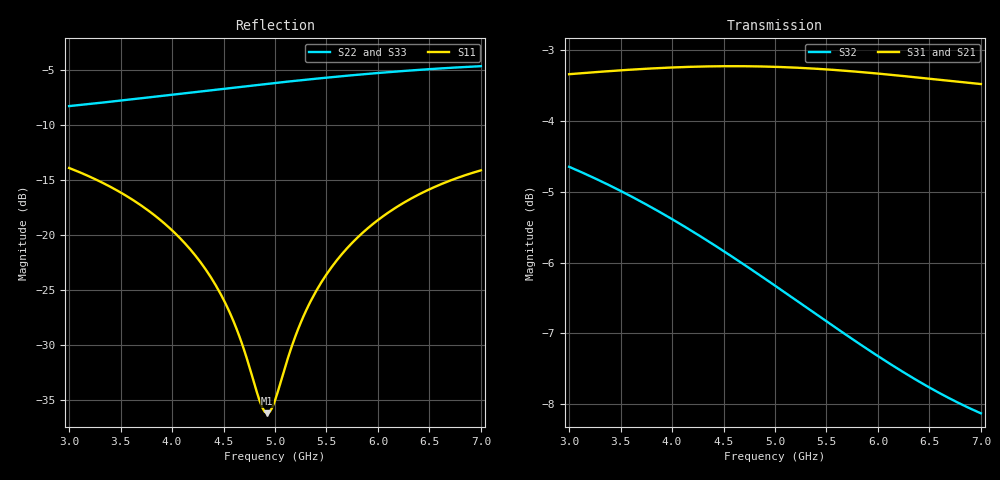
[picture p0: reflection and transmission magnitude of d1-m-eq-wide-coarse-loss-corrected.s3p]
! yapnr Order 0 prediction d1-m-eq-wide-coarse: predictions/D1/variants/d1-star-m-eq/coarse_dense.s3p, loss-corrected
! substrate M-eq; coupon model OSHPARK-4L-FR408HR; correction: ratio (port line)
! |S21|, |S31| (and S12, S13) scaled, phases kept; 50 ohm, e^(+jwt)
# GHz S RI R 50
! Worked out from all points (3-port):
!   161 points, 3 GHz to 7 GHz, reference 50 ohm
!   strongest paths, dB at 3 GHz, 4 GHz, 5 GHz, 6 GHz, 7 GHz:
!     S31: -3.3, -3.2, -3.2, -3.3, -3.5
!     S21: -3.3, -3.2, -3.2, -3.3, -3.5
!     S32: -4.6, -5.4, -6.3, -7.3, -8.1
!   lowest |S11| = -36.2 dB at 4.925 GHz (marker M1), VSWR 1.03, Z = 48.5 + j0.238 ohm
!   |S11| at or under -10 dB: start of sweep to end of sweep
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3  -0.1221 0.1605  0.1067 -0.6724  0.1067 -0.6724
   0.1066 -0.6723  0.0917 0.3747  -0.1498 -0.5661
   0.1066 -0.6723  -0.1498 -0.5661  0.0917 0.3747
3.7  -0.0571 0.1237  -0.1265 -0.6748  -0.1265 -0.6748
     -0.1265 -0.6747  0.2541 0.333  -0.3444 -0.4331
     -0.1265 -0.6747  -0.3444 -0.4331  0.2541 0.333
4.225  -0.0247 0.0769  -0.2971 -0.6219  -0.2971 -0.6219
       -0.2971 -0.6218  0.3648 0.2586  -0.4346 -0.296
       -0.2971 -0.6218  -0.4346 -0.296  0.3648 0.2586
4.55  -0.015 0.0429  -0.3939 -0.5662  -0.3939 -0.5662
      -0.3939 -0.5661  0.4227 0.1952  -0.4645 -0.2055
      -0.3939 -0.5661  -0.4645 -0.2055  0.4227 0.1952
4.925  -0.0152 0.00245  -0.4923 -0.4825  -0.4923 -0.4825
       -0.4922 -0.4824  0.4751 0.1081  -0.476 -0.1029
       -0.4922 -0.4824  -0.476 -0.1029  0.4751 0.1081
5  -0.0168 -0.00547  -0.5098 -0.4635  -0.5098 -0.4635
   -0.5098 -0.4634  0.4834 0.0892  -0.4756 -0.0831
   -0.5098 -0.4634  -0.4756 -0.0831  0.4834 0.0892
5.3  -0.0278 -0.0355  -0.5721 -0.3813  -0.5721 -0.3813
     -0.5721 -0.3812  0.5085 0.00965  -0.4662 -0.00743
     -0.5721 -0.3812  -0.4662 -0.00743  0.5085 0.00965
5.675  -0.0515 -0.0669  -0.6304 -0.2673  -0.6304 -0.2673
       -0.6303 -0.2672  0.5204 -0.0955  -0.4398 0.0772
       -0.6303 -0.2672  -0.4398 0.0772  0.5204 -0.0955
6.25  -0.1033 -0.0946  -0.6742 -0.079  -0.6742 -0.079
      -0.6741 -0.0789  0.4947 -0.257  -0.3775 0.1825
      -0.6741 -0.0789  -0.3775 0.1825  0.4947 -0.257
7  -0.1778 -0.0843  -0.6494 0.1651  -0.6494 0.1651
   -0.6493 0.1652  0.3876 -0.4397  -0.2769 0.2779
   -0.6493 0.1652  -0.2769 0.2779  0.3876 -0.4397
